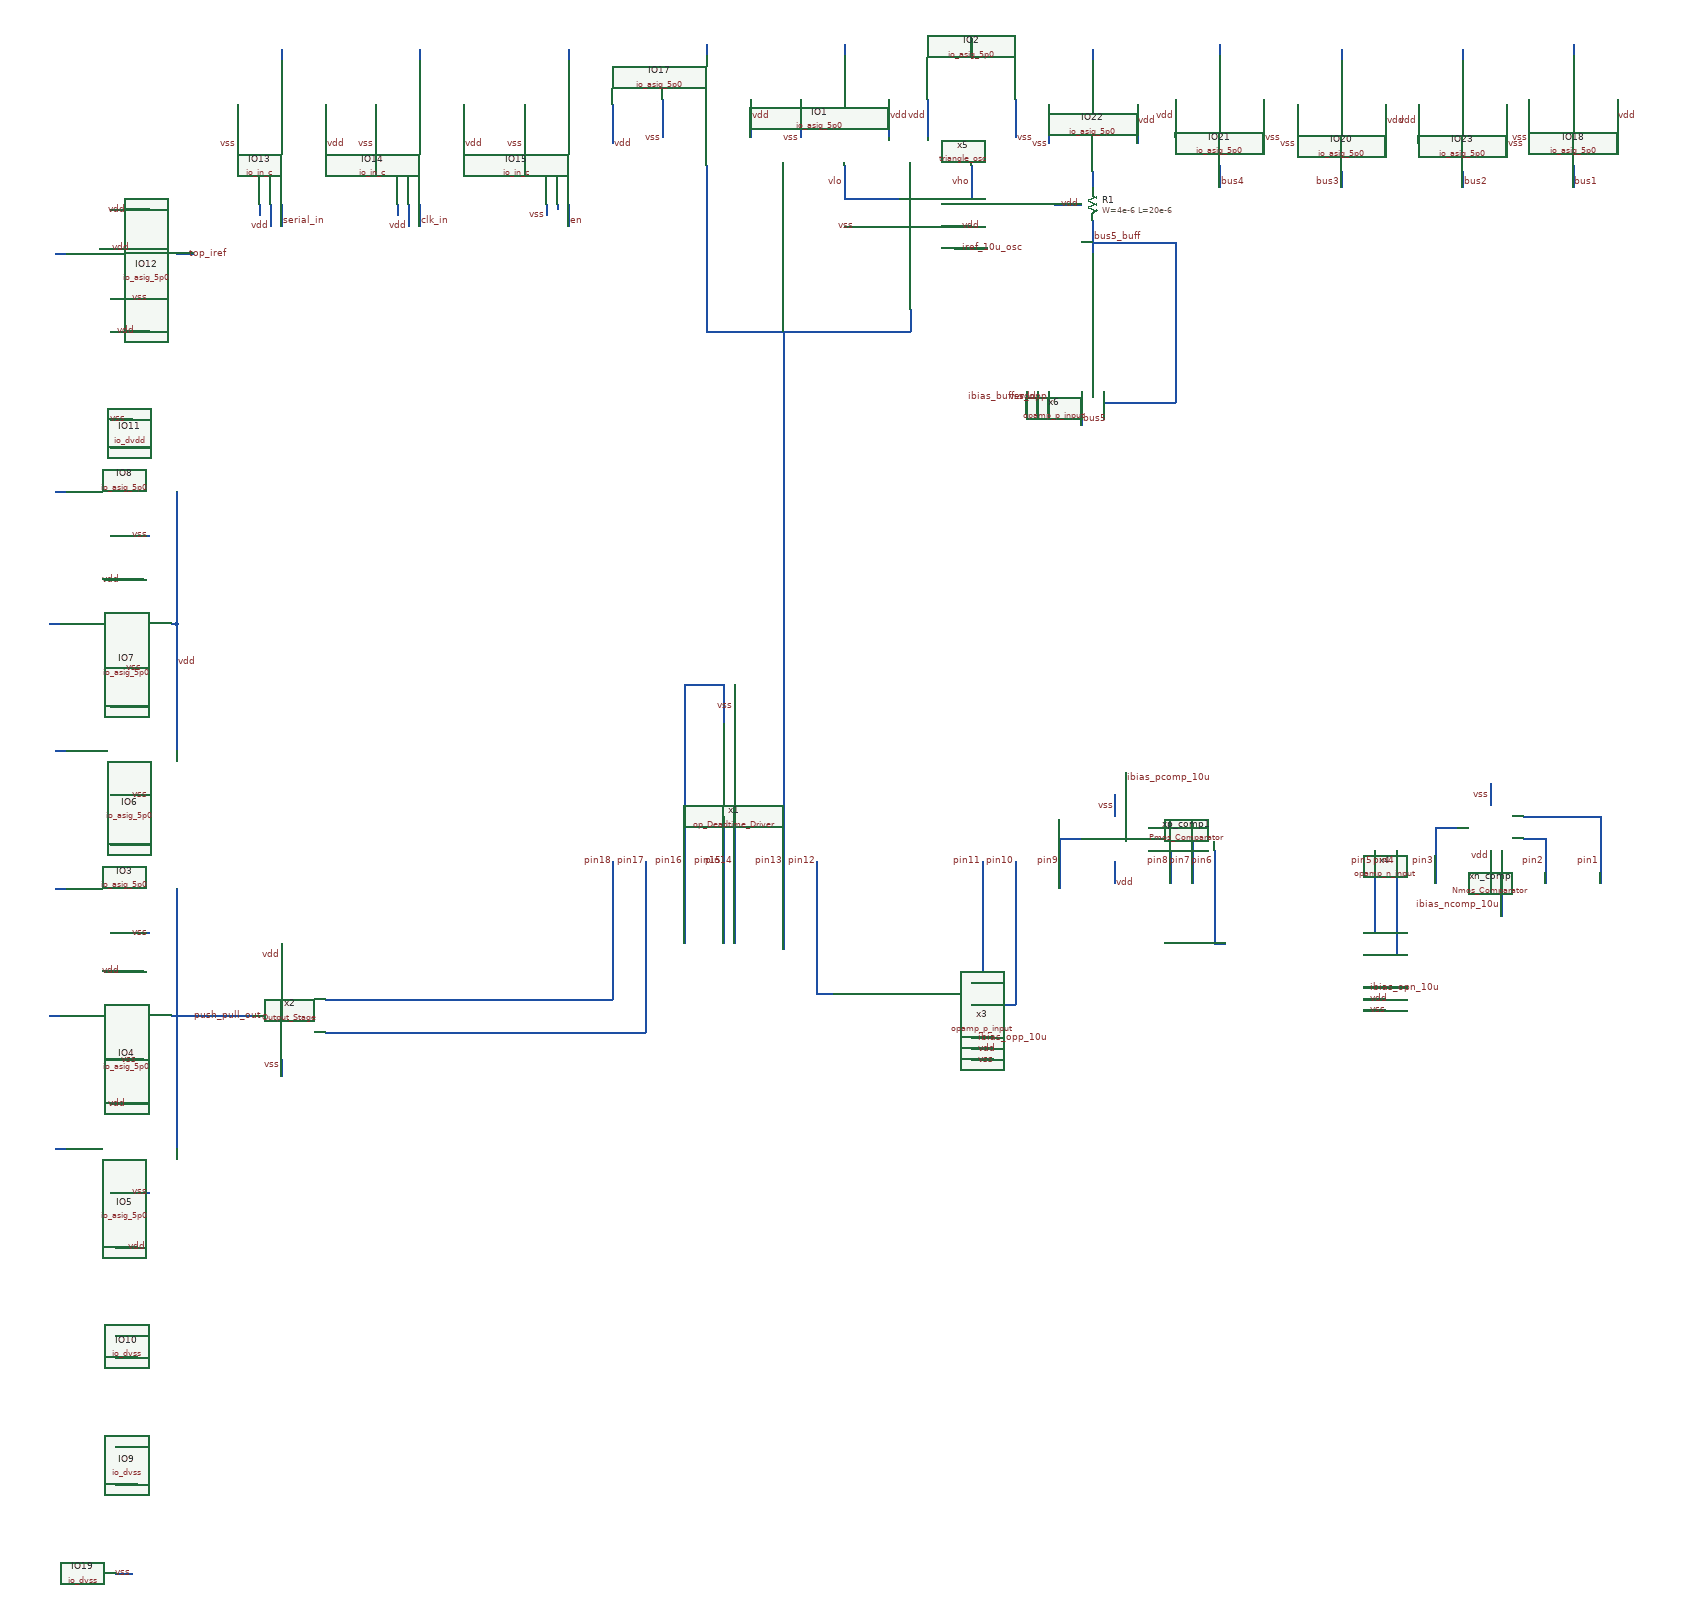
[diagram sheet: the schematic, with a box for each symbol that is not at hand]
v {xschem version=3.4.7 file_version=1.2}
G {}
K {}
V {}
S {}
E {}
N 1850 -2800 1900 -2800 {lab=vho}
N 1900 -2860 1900 -2800 {lab=vho}
N 1670 -2860 1670 -2800 {lab=vlo}
N 1590 -2980 1590 -2940 {lab=vss}
N 1820 -2980 1820 -2940 {lab=vdd}
N 1980 -2980 1980 -2940 {lab=vss}
N 1980 -2940 1980 -2910 {lab=vss}
N 1820 -2940 1820 -2910 {lab=vdd}
N 1750 -2980 1750 -2910 {lab=vdd}
N 1590 -2940 1590 -2910 {lab=vss}
N 1900 -3090 1900 -3060 {lab=#net1}
N 1670 -3080 1670 -3060 {lab=#net2}
N 340 -1470 380 -1470 {lab=vss}
N 340 -1630 410 -1630 {lab=vdd}
N 380 -1470 410 -1470 {lab=vss}
N 240 -1550 260 -1550 {lab=#net3}
N 330 -1240 370 -1240 {lab=vss}
N 330 -1400 400 -1400 {lab=vdd}
N 370 -1240 400 -1240 {lab=vss}
N 230 -1320 250 -1320 {lab=#net4}
N 340 -1000 380 -1000 {lab=vss}
N 340 -1160 410 -1160 {lab=vdd}
N 380 -1000 410 -1000 {lab=vss}
N 240 -1080 260 -1080 {lab=#net5}
N 450 -1320 600 -1320 {lab=push_pull_out}
N 460 -1550 460 -1320 {lab=push_pull_out}
N 460 -1320 460 -1080 {lab=push_pull_out}
N 340 -1720 380 -1720 {lab=vss}
N 340 -1880 410 -1880 {lab=vdd}
N 380 -1720 410 -1720 {lab=vss}
N 240 -1800 260 -1800 {lab=#net6}
N 330 -1950 370 -1950 {lab=vss}
N 330 -2110 400 -2110 {lab=vdd}
N 370 -1950 400 -1950 {lab=vss}
N 230 -2030 250 -2030 {lab=#net7}
N 340 -2190 380 -2190 {lab=vss}
N 340 -2350 410 -2350 {lab=vdd}
N 380 -2190 410 -2190 {lab=vss}
N 240 -2270 260 -2270 {lab=#net8}
N 460 -2030 460 -1800 {lab=vdd}
N 460 -2270 460 -2030 {lab=vdd}
N 350 -310 380 -310 {lab=vss}
N 450 -2030 460 -2030 {lab=vdd}
N 340 -2620 380 -2620 {lab=vss}
N 340 -2780 410 -2780 {lab=vdd}
N 380 -2620 410 -2620 {lab=vss}
N 240 -2700 260 -2700 {lab=#net9}
N 460 -2700 490 -2700 {lab=top_iref}
N 570 -2970 570 -2930 {lab=vss}
N 570 -2930 570 -2900 {lab=vss}
N 650 -3070 650 -3050 {lab=#net10}
N 1340 -2980 1340 -2940 {lab=vss}
N 1500 -2980 1500 -2910 {lab=vdd}
N 1340 -2940 1340 -2910 {lab=vss}
N 1420 -3080 1420 -3060 {lab=#net11}
N 1420 -2860 1420 -2840 {lab=pin13}
N 2910 -2980 2910 -2940 {lab=vss}
N 3070 -2980 3070 -2910 {lab=vdd}
N 2910 -2940 2910 -2910 {lab=vss}
N 2990 -3080 2990 -3060 {lab=#net12}
N 2490 -2970 2490 -2930 {lab=vss}
N 2650 -2970 2650 -2900 {lab=vdd}
N 2490 -2930 2490 -2900 {lab=vss}
N 2570 -3070 2570 -3050 {lab=#net13}
N 2430 -2980 2430 -2940 {lab=vss}
N 2270 -2980 2270 -2910 {lab=vdd}
N 2430 -2940 2430 -2910 {lab=vss}
N 2350 -3080 2350 -3060 {lab=#net14}
N 2040 -2970 2040 -2930 {lab=vss}
N 2200 -2970 2200 -2900 {lab=vdd}
N 2040 -2930 2040 -2900 {lab=vss}
N 2120 -3070 2120 -3050 {lab=#net15}
N 2350 -2860 2350 -2850 {lab=bus4}
N 2870 -2970 2870 -2930 {lab=vss}
N 2710 -2970 2710 -2900 {lab=vdd}
N 2870 -2930 2870 -2900 {lab=vss}
N 2790 -3070 2790 -3050 {lab=#net16}
N 2120 -2850 2120 -2830 {lab=#net17}
N 2570 -2850 2570 -2820 {lab=bus3}
N 2790 -2850 2790 -2820 {lab=bus2}
N 2990 -2860 2990 -2830 {lab=bus1}
N 2120 -2750 2120 -2700 {lab=bus5_buff}
N 2140 -2450 2140 -2430 {lab=bus5_buff}
N 2140 -2430 2270 -2430 {lab=bus5_buff}
N 2270 -2710 2270 -2430 {lab=bus5_buff}
N 2120 -2720 2270 -2720 {lab=bus5_buff}
N 2270 -2720 2270 -2710 {lab=bus5_buff}
N 650 -1450 650 -1400 {lab=vdd}
N 350 -470 390 -470 {lab=vdd}
N 350 -540 380 -540 {lab=vss}
N 350 -700 390 -700 {lab=vdd}
N 350 -740 380 -740 {lab=vss}
N 350 -900 390 -900 {lab=vdd}
N 340 -2400 370 -2400 {lab=vss}
N 320 -2710 360 -2710 {lab=vdd}
N 370 -2400 380 -2400 {lab=vss}
N 340 -2560 410 -2560 {lab=vdd}
N 730 -2970 730 -2900 {lab=vdd}
N 650 -2790 650 -2750 {lab=serial_in}
N 630 -2790 630 -2780 {lab=vdd}
N 630 -2780 630 -2750 {lab=vdd}
N 610 -2790 610 -2770 {lab=#net18}
N 820 -2970 820 -2930 {lab=vss}
N 820 -2930 820 -2900 {lab=vss}
N 900 -3070 900 -3050 {lab=#net19}
N 980 -2970 980 -2900 {lab=vdd}
N 900 -2790 900 -2750 {lab=clk_in}
N 880 -2790 880 -2780 {lab=vdd}
N 880 -2780 880 -2750 {lab=vdd}
N 860 -2790 860 -2770 {lab=#net20}
N 1090 -2970 1090 -2930 {lab=vss}
N 1090 -2930 1090 -2900 {lab=vss}
N 1170 -3070 1170 -3050 {lab=#net21}
N 1250 -2970 1250 -2900 {lab=vdd}
N 1170 -2790 1170 -2750 {lab=en}
N 1150 -2790 1150 -2780 {lab=#net22}
N 1130 -2790 1130 -2770 {lab=vss}
N 1670 -2750 1710 -2750 {lab=vss}
N 1870 -2750 1900 -2750 {lab=vdd}
N 1880 -2710 1930 -2710 {lab=iref_10u_osc}
N 1870 -2710 1880 -2710 {lab=iref_10u_osc}
N 1790 -2600 1790 -2560 {lab=pin13}
N 2000 -2450 2000 -2410 {lab=vss}
N 2020 -2450 2020 -2410 {lab=vdd}
N 2040 -2450 2040 -2410 {lab=ibias_buffer_opp}
N 2100 -2450 2100 -2390 {lab=bus5}
N 1900 -1240 1940 -1240 {lab=vss}
N 1900 -1260 1940 -1260 {lab=vdd}
N 1900 -1280 1940 -1280 {lab=ibias_opp_10u}
N 2610 -1330 2650 -1330 {lab=vss}
N 2610 -1350 2650 -1350 {lab=vdd}
N 2610 -1370 2650 -1370 {lab=ibias_opn_10u}
N 1900 -1380 1920 -1380 {lab=pin11}
N 1920 -1500 1920 -1380 {lab=pin11}
N 1980 -1600 1980 -1340 {lab=pin10}
N 1920 -1600 1920 -1500 {lab=pin11}
N 1620 -1600 1620 -1360 {lab=pin12}
N 2610 -1470 2630 -1470 {lab=pin5}
N 2630 -1590 2630 -1470 {lab=pin5}
N 2610 -1430 2650 -1430 {lab=pin4}
N 2650 -1370 2690 -1370 {lab=ibias_opn_10u}
N 2160 -1720 2160 -1680 {lab=vss}
N 2160 -1600 2160 -1560 {lab=vdd}
N 2160 -1720 2160 -1680 {lab=vss}
N 2160 -1600 2160 -1560 {lab=vdd}
N 2180 -1720 2180 -1680 {lab=ibias_pcomp_10u}
N 2180 -1760 2180 -1720 {lab=ibias_pcomp_10u}
N 2060 -1640 2100 -1640 {lab=pin9}
N 2220 -1620 2260 -1620 {lab=pin8}
N 2900 -1640 2940 -1640 {lab=pin2}
N 2900 -1680 3040 -1680 {lab=pin1}
N 2740 -1660 2780 -1660 {lab=pin3}
N 2840 -1740 2840 -1700 {lab=vss}
N 2840 -1740 2840 -1700 {lab=vss}
N 2860 -1620 2860 -1580 {lab=ibias_ncomp_10u}
N 1470 -1920 1470 -1850 {lab=vss}
N 1450 -1920 1450 -1850 {lab=pin16}
N 1380 -1920 1380 -1580 {lab=pin16}
N 1450 -1680 1450 -1580 {lab=pin15}
N 1420 -2840 1420 -2560 {lab=pin13}
N 1420 -2560 1790 -2560 {lab=pin13}
N 1670 -2800 1770 -2800 {lab=vlo}
N 1810 -2800 1850 -2800 {lab=vho}
N 2350 -2860 2350 -2820 {lab=bus4}
N 1450 -1580 1450 -1450 {lab=pin15}
N 1380 -1580 1380 -1450 {lab=pin16}
N 1470 -1680 1470 -1450 {lab=pin14}
N 650 -1240 650 -1210 {lab=vss}
N 730 -1350 1250 -1350 {lab=pin18}
N 1250 -1450 1250 -1350 {lab=pin18}
N 730 -1290 1310 -1290 {lab=pin17}
N 1310 -1440 1310 -1290 {lab=pin17}
N 1310 -1450 1310 -1440 {lab=pin17}
N 1250 -1600 1250 -1450 {lab=pin18}
N 1310 -1600 1310 -1450 {lab=pin17}
N 2060 -1640 2060 -1580 {lab=pin9}
N 2260 -1620 2260 -1560 {lab=pin8}
N 2300 -1660 2300 -1560 {lab=pin7}
N 2740 -1660 2740 -1560 {lab=pin3}
N 2940 -1640 2940 -1560 {lab=pin2}
N 3040 -1680 3040 -1560 {lab=pin1}
N 2860 -1580 2860 -1500 {lab=ibias_ncomp_10u}
N 2670 -1590 2670 -1430 {lab=pin4}
N 2340 -1620 2340 -1450 {lab=pin6}
N 2630 -1620 2630 -1590 {lab=pin5}
N 2670 -1620 2670 -1590 {lab=pin4}
N 2840 -1620 2840 -1590 {lab=vdd}
N 1560 -2560 1560 -1440 {lab=pin13}
N 1380 -1920 1450 -1920 {lab=pin16}
N 1620 -1360 1650 -1360 {lab=pin12}
N 1900 -1340 1980 -1340 {lab=pin10}
N 2060 -1580 2060 -1550 {lab=pin9}
N 2650 -1430 2670 -1430 {lab=pin4}
N 2340 -1450 2360 -1450 {lab=pin6}
N 2220 -1660 2300 -1660 {lab=pin7}
N 2990 -2830 2990 -2820 {lab=bus1}
N 2120 -2760 2120 -2750 {lab=bus5_buff}
N 2120 -2830 2120 -2820 {lab=#net17}
N 2050 -2790 2100 -2790 {lab=#net23}
C {title.sym} 70 30 0 0 {name=l1 author=", X.J. Lee, Christopher O Amankwaa"}
C {libs/core_analog/Comparator/Nmos_Comparator.sym} 2880 -1620 2 0 {name=xn_comp}
C {libs/core_analog/op_Deadtime_Driver/op_Deadtime_Driver.sym} 1460 -1700 3 1 {name=x1}
C {libs/core_analog/Output_Stage/Output_Stage.sym} 680 -1320 0 1 {name=x2}
C {libs/core_analog/opamp/opamp_p_input.sym} 1880 -1450 0 1 {name=x3}
C {libs/core_analog/opamp/opamp_n_input.sym} 2590 -1540 0 1 {name=x4}
C {libs/core_analog/oscillator/triangle_osc.sym} 1850 -2780 1 0 {name=x5}
C {libs/core_analog/opamp/opamp_p_input.sym} 2210 -2470 1 1 {name=x6}
C {libs/core_analog/Chipathon2025_pads/xschem/symbols/io_asig_5p0.sym} 1590 -3060 1 0 {name=IO1
model=gf180mcu_fd_io__asig_5p0_extracted
spiceprefix=X
}
C {libs/core_analog/Chipathon2025_pads/xschem/symbols/io_asig_5p0.sym} 1980 -3060 3 1 {name=IO2
model=gf180mcu_fd_io__asig_5p0_extracted
spiceprefix=X
}
C {lab_wire.sym} 1590 -2910 0 0 {name=p1 sig_type=std_logic lab=vss}
C {lab_wire.sym} 1980 -2910 0 1 {name=p2 sig_type=std_logic lab=vss}
C {lab_wire.sym} 1820 -2950 0 0 {name=p3 sig_type=std_logic lab=vdd}
C {lab_wire.sym} 1750 -2950 0 1 {name=p4 sig_type=std_logic lab=vdd}
C {noconn.sym} 1750 -3090 3 1 {name=l2}
C {noconn.sym} 1670 -3080 1 0 {name=l3}
C {lab_wire.sym} 1900 -2830 0 0 {name=p5 sig_type=std_logic lab=vho}
C {lab_wire.sym} 1670 -2830 0 0 {name=p6 sig_type=std_logic lab=vlo}
C {libs/core_analog/Chipathon2025_pads/xschem/symbols/io_asig_5p0.sym} 260 -1470 0 0 {name=IO3
model=gf180mcu_fd_io__asig_5p0_extracted
spiceprefix=X
}
C {lab_wire.sym} 410 -1470 3 0 {name=p7 sig_type=std_logic lab=vss}
C {lab_wire.sym} 370 -1630 3 1 {name=p8 sig_type=std_logic lab=vdd}
C {noconn.sym} 240 -1550 2 1 {name=l4}
C {libs/core_analog/Chipathon2025_pads/xschem/symbols/io_asig_5p0.sym} 250 -1240 0 0 {name=IO4
model=gf180mcu_fd_io__asig_5p0_extracted
spiceprefix=X
}
C {lab_wire.sym} 390 -1240 2 1 {name=p9 sig_type=std_logic lab=vss}
C {lab_wire.sym} 360 -1400 3 1 {name=p10 sig_type=std_logic lab=vdd}
C {noconn.sym} 230 -1320 2 1 {name=l5}
C {libs/core_analog/Chipathon2025_pads/xschem/symbols/io_asig_5p0.sym} 260 -1000 0 0 {name=IO5
model=gf180mcu_fd_io__asig_5p0_extracted
spiceprefix=X
}
C {lab_wire.sym} 410 -1000 3 0 {name=p11 sig_type=std_logic lab=vss}
C {lab_wire.sym} 370 -1160 3 1 {name=p12 sig_type=std_logic lab=vdd}
C {noconn.sym} 240 -1080 2 1 {name=l6}
C {lab_wire.sym} 490 -1320 0 1 {name=p13 sig_type=std_logic lab=push_pull_out}
C {libs/core_analog/Chipathon2025_pads/xschem/symbols/io_asig_5p0.sym} 260 -1720 0 0 {name=IO6
model=gf180mcu_fd_io__asig_5p0_extracted
spiceprefix=X
}
C {lab_wire.sym} 410 -1720 3 0 {name=p14 sig_type=std_logic lab=vss}
C {lab_wire.sym} 370 -1880 3 1 {name=p15 sig_type=std_logic lab=vdd}
C {noconn.sym} 240 -1800 0 0 {name=l7}
C {libs/core_analog/Chipathon2025_pads/xschem/symbols/io_asig_5p0.sym} 250 -1950 0 0 {name=IO7
model=gf180mcu_fd_io__asig_5p0_extracted
spiceprefix=X
}
C {lab_wire.sym} 400 -1950 3 0 {name=p16 sig_type=std_logic lab=vss}
C {lab_wire.sym} 360 -2110 3 1 {name=p17 sig_type=std_logic lab=vdd}
C {noconn.sym} 230 -2030 0 0 {name=l8}
C {libs/core_analog/Chipathon2025_pads/xschem/symbols/io_asig_5p0.sym} 260 -2190 0 0 {name=IO8
model=gf180mcu_fd_io__asig_5p0_extracted
spiceprefix=X
}
C {lab_wire.sym} 410 -2190 3 0 {name=p18 sig_type=std_logic lab=vss}
C {lab_wire.sym} 370 -2350 3 1 {name=p19 sig_type=std_logic lab=vdd}
C {noconn.sym} 240 -2270 0 0 {name=l9}
C {lab_wire.sym} 460 -1960 2 0 {name=p20 sig_type=std_logic lab=vdd}
C {lab_wire.sym} 380 -310 0 0 {name=p25 sig_type=std_logic lab=vss}
C {lab_wire.sym} 370 -470 0 1 {name=p26 sig_type=std_logic lab=vdd}
C {libs/core_analog/Chipathon2025_pads/xschem/symbols/io_asig_5p0.sym} 260 -2620 0 0 {name=IO12
model=gf180mcu_fd_io__asig_5p0_extracted
spiceprefix=X
}
C {lab_wire.sym} 410 -2620 3 0 {name=p28 sig_type=std_logic lab=vss}
C {lab_wire.sym} 370 -2780 3 1 {name=p29 sig_type=std_logic lab=vdd}
C {noconn.sym} 240 -2700 0 0 {name=l13}
C {lab_wire.sym} 480 -2700 2 0 {name=p33 sig_type=std_logic lab=top_iref}
C {lab_wire.sym} 570 -2900 0 0 {name=p38 sig_type=std_logic lab=vss}
C {noconn.sym} 650 -3070 1 0 {name=l17}
C {libs/core_analog/Chipathon2025_pads/xschem/symbols/io_asig_5p0.sym} 1340 -3060 1 0 {name=IO17
model=gf180mcu_fd_io__asig_5p0_extracted
spiceprefix=X
}
C {lab_wire.sym} 1340 -2910 0 0 {name=p43 sig_type=std_logic lab=vss}
C {lab_wire.sym} 1500 -2950 0 1 {name=p44 sig_type=std_logic lab=vdd}
C {noconn.sym} 1420 -3080 1 0 {name=l18}
C {libs/core_analog/Chipathon2025_pads/xschem/symbols/io_asig_5p0.sym} 2910 -3060 1 0 {name=IO18
model=gf180mcu_fd_io__asig_5p0_extracted
spiceprefix=X
}
C {lab_wire.sym} 2910 -2910 0 0 {name=p46 sig_type=std_logic lab=vss}
C {lab_wire.sym} 3070 -2950 0 1 {name=p49 sig_type=std_logic lab=vdd}
C {libs/core_analog/Chipathon2025_pads/xschem/symbols/io_asig_5p0.sym} 2490 -3050 1 0 {name=IO20
model=gf180mcu_fd_io__asig_5p0_extracted
spiceprefix=X
}
C {lab_wire.sym} 2490 -2900 0 0 {name=p50 sig_type=std_logic lab=vss}
C {lab_wire.sym} 2650 -2940 0 1 {name=p51 sig_type=std_logic lab=vdd}
C {noconn.sym} 2570 -3070 1 0 {name=l19}
C {libs/core_analog/Chipathon2025_pads/xschem/symbols/io_asig_5p0.sym} 2430 -3060 3 1 {name=IO21
model=gf180mcu_fd_io__asig_5p0_extracted
spiceprefix=X
}
C {lab_wire.sym} 2430 -2910 0 1 {name=p52 sig_type=std_logic lab=vss}
C {lab_wire.sym} 2270 -2950 0 0 {name=p53 sig_type=std_logic lab=vdd}
C {libs/core_analog/Chipathon2025_pads/xschem/symbols/io_asig_5p0.sym} 2040 -3050 1 0 {name=IO22
model=gf180mcu_fd_io__asig_5p0_extracted
spiceprefix=X
}
C {lab_wire.sym} 2040 -2900 0 0 {name=p54 sig_type=std_logic lab=vss}
C {lab_wire.sym} 2200 -2940 0 1 {name=p55 sig_type=std_logic lab=vdd}
C {noconn.sym} 2120 -3070 1 0 {name=l20}
C {lab_wire.sym} 2350 -2830 0 1 {name=p56 sig_type=std_logic lab=bus4}
C {libs/core_analog/Chipathon2025_pads/xschem/symbols/io_asig_5p0.sym} 2870 -3050 3 1 {name=IO23
model=gf180mcu_fd_io__asig_5p0_extracted
spiceprefix=X
}
C {lab_wire.sym} 2870 -2900 0 1 {name=p57 sig_type=std_logic lab=vss}
C {lab_wire.sym} 2710 -2940 0 0 {name=p58 sig_type=std_logic lab=vdd}
C {noconn.sym} 2790 -3070 3 1 {name=l21}
C {lab_wire.sym} 2100 -2400 0 1 {name=p59 sig_type=std_logic lab=bus5}
C {lab_wire.sym} 2570 -2830 0 0 {name=p60 sig_type=std_logic lab=bus3}
C {lab_wire.sym} 2790 -2830 0 1 {name=p61 sig_type=std_logic lab=bus2}
C {lab_wire.sym} 2990 -2830 0 1 {name=p62 sig_type=std_logic lab=bus1}
C {noconn.sym} 2990 -3080 3 1 {name=l22}
C {noconn.sym} 2350 -3080 3 1 {name=l23}
C {lab_wire.sym} 650 -1430 0 0 {name=p47 sig_type=std_logic lab=vdd}
C {libs/core_analog/Chipathon2025_pads/xschem/symbols/io_dvss.sym} 270 -310 0 0 {name=IO19
model=gf180mcu_fd_io__dvss
spiceprefix=X
}
C {lab_wire.sym} 380 -540 0 0 {name=p21 sig_type=std_logic lab=vss}
C {lab_wire.sym} 370 -700 0 1 {name=p22 sig_type=std_logic lab=vdd}
C {libs/core_analog/Chipathon2025_pads/xschem/symbols/io_dvss.sym} 270 -540 0 0 {name=IO9
model=gf180mcu_fd_io__dvss
spiceprefix=X
}
C {lab_wire.sym} 380 -740 0 0 {name=p23 sig_type=std_logic lab=vss}
C {lab_wire.sym} 370 -900 0 1 {name=p24 sig_type=std_logic lab=vdd}
C {libs/core_analog/Chipathon2025_pads/xschem/symbols/io_dvss.sym} 270 -740 0 0 {name=IO10
model=gf180mcu_fd_io__dvss
spiceprefix=X
}
C {libs/core_analog/Chipathon2025_pads/xschem/symbols/io_dvdd.sym} 260 -2400 0 0 {name=IO11
model=gf180mcu_fd_io__dvdd
spiceprefix=X
}
C {lab_wire.sym} 370 -2400 0 0 {name=p27 sig_type=std_logic lab=vss}
C {lab_wire.sym} 340 -2710 0 1 {name=p30 sig_type=std_logic lab=vdd}
C {lab_wire.sym} 350 -2560 0 1 {name=p31 sig_type=std_logic lab=vdd}
C {libs/core_analog/Chipathon2025_pads/xschem/symbols/io_in_c.sym} 570 -3050 1 0 {name=IO13
model=gf180mcu_fd_io__in_c
spiceprefix=X
}
C {lab_wire.sym} 730 -2900 0 1 {name=p32 sig_type=std_logic lab=vdd}
C {lab_wire.sym} 650 -2760 0 1 {name=p35 sig_type=std_logic lab=serial_in
}
C {lab_wire.sym} 630 -2750 2 1 {name=p36 sig_type=std_logic lab=vdd}
C {noconn.sym} 610 -2770 3 0 {name=l10}
C {lab_wire.sym} 820 -2900 0 0 {name=p37 sig_type=std_logic lab=vss}
C {noconn.sym} 900 -3070 1 0 {name=l11}
C {libs/core_analog/Chipathon2025_pads/xschem/symbols/io_in_c.sym} 820 -3050 1 0 {name=IO14
model=gf180mcu_fd_io__in_c
spiceprefix=X
}
C {lab_wire.sym} 980 -2900 0 1 {name=p39 sig_type=std_logic lab=vdd}
C {lab_wire.sym} 900 -2760 0 1 {name=p40 sig_type=std_logic lab=clk_in
}
C {lab_wire.sym} 880 -2750 2 1 {name=p41 sig_type=std_logic lab=vdd}
C {noconn.sym} 860 -2770 3 0 {name=l12}
C {lab_wire.sym} 1090 -2900 0 0 {name=p42 sig_type=std_logic lab=vss}
C {noconn.sym} 1170 -3070 1 0 {name=l14}
C {libs/core_analog/Chipathon2025_pads/xschem/symbols/io_in_c.sym} 1090 -3050 1 0 {name=IO15
model=gf180mcu_fd_io__in_c
spiceprefix=X
}
C {lab_wire.sym} 1250 -2900 0 1 {name=p48 sig_type=std_logic lab=vdd}
C {lab_wire.sym} 1170 -2760 0 1 {name=p63 sig_type=std_logic lab=en}
C {lab_wire.sym} 1130 -2770 0 0 {name=p34 sig_type=std_logic lab=vss}
C {noconn.sym} 1150 -2780 3 0 {name=l15}
C {lab_wire.sym} 1690 -2750 0 0 {name=p64 sig_type=std_logic lab=vss}
C {lab_wire.sym} 1880 -2750 0 1 {name=p65 sig_type=std_logic lab=vdd}
C {lab_wire.sym} 1880 -2710 0 1 {name=p66 sig_type=std_logic lab=iref_10u_osc}
C {lab_wire.sym} 2020 -2440 3 0 {name=p67 sig_type=std_logic lab=vdd}
C {lab_wire.sym} 2000 -2440 3 0 {name=p68 sig_type=std_logic lab=vss}
C {lab_wire.sym} 2040 -2440 3 0 {name=p69 sig_type=std_logic lab=ibias_buffer_opp}
C {lab_wire.sym} 1910 -1260 2 0 {name=p70 sig_type=std_logic lab=vdd}
C {lab_wire.sym} 1910 -1240 2 0 {name=p71 sig_type=std_logic lab=vss}
C {lab_wire.sym} 1910 -1280 0 1 {name=p72 sig_type=std_logic lab=ibias_opp_10u}
C {lab_wire.sym} 2620 -1350 2 0 {name=p73 sig_type=std_logic lab=vdd}
C {lab_wire.sym} 2620 -1330 2 0 {name=p74 sig_type=std_logic lab=vss}
C {lab_wire.sym} 2620 -1370 0 1 {name=p75 sig_type=std_logic lab=ibias_opn_10u}
C {lab_wire.sym} 2160 -1560 0 1 {name=p76 sig_type=std_logic lab=vdd}
C {lab_wire.sym} 2180 -1750 2 0 {name=p78 sig_type=std_logic lab=ibias_pcomp_10u}
C {libs/core_analog/Comparator/Pmos_Comparator.sym} 2200 -1600 2 0 {name=xp_comp1}
C {lab_wire.sym} 2160 -1700 0 0 {name=p80 sig_type=std_logic lab=vss}
C {lab_wire.sym} 2840 -1720 0 0 {name=p82 sig_type=std_logic lab=vss}
C {lab_wire.sym} 2840 -1610 2 1 {name=p83 sig_type=std_logic lab=vdd}
C {lab_wire.sym} 2860 -1520 2 1 {name=p85 sig_type=std_logic lab=ibias_ncomp_10u}
C {lab_wire.sym} 1470 -1880 1 0 {name=p86 sig_type=std_logic lab=vss}
C {lab_wire.sym} 1560 -1600 3 0 {name=p87 sig_type=std_logic lab=pin13}
C {lab_wire.sym} 1470 -1600 1 1 {name=p45 sig_type=std_logic lab=pin14}
C {lab_wire.sym} 1450 -1600 3 0 {name=p88 sig_type=std_logic lab=pin15}
C {lab_wire.sym} 1380 -1600 1 1 {name=p89 sig_type=std_logic lab=pin16}
C {lab_wire.sym} 1620 -1600 1 1 {name=p90 sig_type=std_logic lab=pin12}
C {lab_wire.sym} 1920 -1600 1 1 {name=p91 sig_type=std_logic lab=pin11}
C {lab_wire.sym} 1980 -1600 1 1 {name=p92 sig_type=std_logic lab=pin10}
C {lab_wire.sym} 2340 -1600 1 1 {name=p93 sig_type=std_logic lab=pin6}
C {lab_wire.sym} 2630 -1600 1 1 {name=p94 sig_type=std_logic lab=pin5}
C {lab_wire.sym} 2670 -1600 1 1 {name=p95 sig_type=std_logic lab=pin4}
C {lab_wire.sym} 2060 -1600 3 0 {name=p96 sig_type=std_logic lab=pin9}
C {lab_wire.sym} 2260 -1600 1 1 {name=p97 sig_type=std_logic lab=pin8}
C {lab_wire.sym} 2300 -1600 1 1 {name=p98 sig_type=std_logic lab=pin7}
C {lab_wire.sym} 2740 -1600 1 1 {name=p99 sig_type=std_logic lab=pin3}
C {lab_wire.sym} 2940 -1600 1 1 {name=p100 sig_type=std_logic lab=pin2}
C {lab_wire.sym} 3040 -1600 1 1 {name=p101 sig_type=std_logic lab=pin1
}
C {lab_wire.sym} 650 -1230 3 0 {name=p102 sig_type=std_logic lab=vss}
C {lab_wire.sym} 1250 -1600 1 1 {name=p103 sig_type=std_logic lab=pin18}
C {lab_wire.sym} 1310 -1600 1 1 {name=p104 sig_type=std_logic lab=pin17
}
C {lab_wire.sym} 2120 -2730 0 1 {name=p77 sig_type=std_logic lab=bus5_buff}
C {symbols/ppolyf_s.sym} 2120 -2790 0 0 {name=R1
W=4e-6
L=20e-6
model=ppolyf_s
spiceprefix=X
m=1}
C {lab_wire.sym} 2060 -2790 0 1 {name=p79 sig_type=std_logic lab=vdd}
